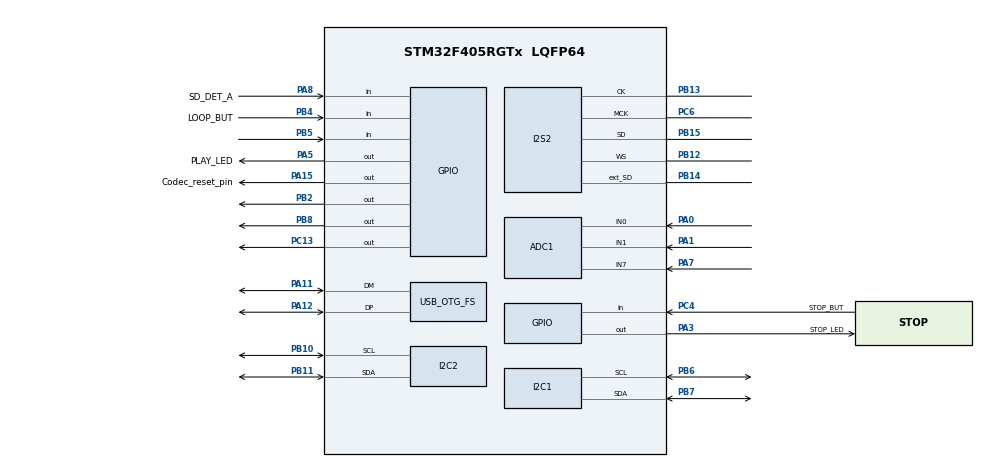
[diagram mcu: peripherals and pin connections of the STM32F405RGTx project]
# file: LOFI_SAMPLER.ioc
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ADC1.Channel-0\#ChannelRegularConversion=ADC_CHANNEL_0
ADC1.Channel-1\#ChannelRegularConversion=ADC_CHANNEL_1
ADC1.Channel-2\#ChannelRegularConversion=ADC_CHANNEL_7
ADC1.ClockPrescaler=ADC_CLOCK_SYNC_PCLK_DIV4
ADC1.DMAContinuousRequests=ENABLE
ADC1.ExternalTrigConv=ADC_EXTERNALTRIGCONV_T2_TRGO
ADC1.NbrOfConversion=3
ADC1.NbrOfConversionFlag=1
ADC1.Rank-0\#ChannelRegularConversion=1
ADC1.Rank-1\#ChannelRegularConversion=2
ADC1.Rank-2\#ChannelRegularConversion=3
ADC1.SamplingTime-0\#ChannelRegularConversion=ADC_SAMPLETIME_144CYCLES
ADC1.SamplingTime-1\#ChannelRegularConversion=ADC_SAMPLETIME_144CYCLES
ADC1.SamplingTime-2\#ChannelRegularConversion=ADC_SAMPLETIME_144CYCLES
ADC1.ScanConvMode=ENABLE
ADC1.master=1
Dma.ADC1.2.Direction=DMA_PERIPH_TO_MEMORY
Dma.ADC1.2.FIFOMode=DMA_FIFOMODE_DISABLE
Dma.ADC1.2.Instance=DMA2_Stream0
Dma.ADC1.2.MemDataAlignment=DMA_MDATAALIGN_HALFWORD
Dma.ADC1.2.MemInc=DMA_MINC_ENABLE
Dma.ADC1.2.Mode=DMA_CIRCULAR
Dma.ADC1.2.PeriphDataAlignment=DMA_PDATAALIGN_HALFWORD
Dma.ADC1.2.PeriphInc=DMA_PINC_DISABLE
Dma.ADC1.2.Priority=DMA_PRIORITY_LOW
Dma.I2S2_EXT_RX.1.Direction=DMA_PERIPH_TO_MEMORY
Dma.I2S2_EXT_RX.1.FIFOMode=DMA_FIFOMODE_DISABLE
Dma.I2S2_EXT_RX.1.Instance=DMA1_Stream3
Dma.I2S2_EXT_RX.1.MemDataAlignment=DMA_MDATAALIGN_HALFWORD
Dma.I2S2_EXT_RX.1.MemInc=DMA_MINC_ENABLE
Dma.I2S2_EXT_RX.1.Mode=DMA_CIRCULAR
Dma.I2S2_EXT_RX.1.PeriphDataAlignment=DMA_PDATAALIGN_HALFWORD
Dma.I2S2_EXT_RX.1.PeriphInc=DMA_PINC_DISABLE
Dma.I2S2_EXT_RX.1.Priority=DMA_PRIORITY_VERY_HIGH
Dma.Request0=SPI2_TX
Dma.Request1=I2S2_EXT_RX
Dma.Request2=ADC1
Dma.SPI2_TX.0.Direction=DMA_MEMORY_TO_PERIPH
Dma.SPI2_TX.0.FIFOMode=DMA_FIFOMODE_DISABLE
Dma.SPI2_TX.0.Instance=DMA1_Stream4
Dma.SPI2_TX.0.MemDataAlignment=DMA_MDATAALIGN_HALFWORD
Dma.SPI2_TX.0.MemInc=DMA_MINC_ENABLE
Dma.SPI2_TX.0.Mode=DMA_CIRCULAR
Dma.SPI2_TX.0.PeriphDataAlignment=DMA_PDATAALIGN_HALFWORD
Dma.SPI2_TX.0.PeriphInc=DMA_PINC_DISABLE
Dma.SPI2_TX.0.Priority=DMA_PRIORITY_VERY_HIGH
I2S2.AudioFreq=I2S_AUDIOFREQ_48K
I2S2.ErrorAudioFreq=1.72 %
I2S2.FullDuplexMode=I2S_FULLDUPLEXMODE_ENABLE
I2S2.Instance=SPI$Index
I2S2.RealAudioFreq=48.828 KHz
I2S2.VirtualMode=I2S_MODE_MASTER
Mcu.Family=STM32F4
Mcu.Name=STM32F405RGTx
Mcu.Package=LQFP64
NVIC.DMA1_Stream3_IRQn=true\:0\:0\:false\:false\:true\:false\:true\:true
NVIC.DMA1_Stream4_IRQn=true\:0\:0\:false\:false\:true\:false\:true\:true
NVIC.DMA2_Stream0_IRQn=true\:0\:0\:false\:false\:true\:false\:true\:true
NVIC.OTG_FS_IRQn=true\:0\:0\:false\:false\:true\:false\:true\:true
NVIC.PriorityGroup=NVIC_PRIORITYGROUP_4
PA0-WKUP.Signal=ADCx_IN0
PA1.Signal=ADCx_IN1
PA11.Mode=Device_Only
PA11.Signal=USB_OTG_FS_DM
PA12.Mode=Device_Only
PA12.Signal=USB_OTG_FS_DP
PA13.Mode=Serial_Wire
PA13.Signal=SYS_JTMS-SWDIO
PA14.Mode=Serial_Wire
PA14.Signal=SYS_JTCK-SWCLK
PA15.GPIO_Label=Codec_reset_pin
PA15.Signal=GPIO_Output
PA3.GPIO_Label=STOP_LED
PA3.Signal=GPIO_Output
PA5.GPIO_Label=PLAY_LED
PA5.Signal=GPIO_Output
PA7.Signal=ADCx_IN7
PA8.GPIO_Label=SD_DET_A
PA8.Signal=GPIO_Input
PB10.Mode=I2C
PB10.Signal=I2C2_SCL
PB11.Mode=I2C
PB11.Signal=I2C2_SDA
PB12.Mode=Full_Duplex_Master
PB12.Signal=I2S2_WS
PB13.Mode=Full_Duplex_Master
PB13.Signal=I2S2_CK
PB14.Mode=Full_Duplex_Master
PB14.Signal=I2S2_ext_SD
PB15.Mode=Full_Duplex_Master
PB15.Signal=I2S2_SD
PB2.Signal=GPIO_Output
PB3.Signal=SYS_JTDO-SWO
PB4.GPIO_Label=LOOP_BUT
PB4.Signal=GPIO_Input
PB5.Signal=GPIO_Input
PB6.Mode=I2C
PB6.Signal=I2C1_SCL
PB7.Mode=I2C
PB7.Signal=I2C1_SDA
PB8.Signal=GPIO_Output
PC13-ANTI_TAMP.Signal=GPIO_Output
PC4.GPIO_Label=STOP_BUT
PC4.Signal=GPIO_Input
PC6.Mode=Master_Clock_Activated
PC6.Signal=I2S2_MCK
PH0-OSC_IN.Mode=HSE-External-Oscillator
PH0-OSC_IN.Signal=RCC_OSC_IN
PH1-OSC_OUT.Mode=HSE-External-Oscillator
PH1-OSC_OUT.Signal=RCC_OSC_OUT
ProjectManager.HeapSize=0x200
ProjectManager.StackSize=0x400
ProjectManager.TargetToolchain=STM32CubeIDE
RCC.48MHZClocksFreq_Value=48000000
RCC.AHBFreq_Value=72000000
RCC.APB1CLKDivider=RCC_HCLK_DIV2
RCC.APB1Freq_Value=36000000
RCC.APB1TimFreq_Value=72000000
RCC.APB2Freq_Value=72000000
RCC.APB2TimFreq_Value=72000000
RCC.CortexFreq_Value=72000000
RCC.HCLKFreq_Value=72000000
RCC.HSE_VALUE=16000000
RCC.HSI_VALUE=16000000
RCC.LSE_VALUE=32768
RCC.PLLI2SN=50
RCC.PLLM=8
RCC.PLLN=72
RCC.PLLQ=3
RCC.SYSCLKFreq_VALUE=72000000
RCC.SYSCLKSource=RCC_SYSCLKSOURCE_PLLCLK
RCC.VCOOutputFreq_Value=144000000
SH.ADCx_IN0.0=ADC1_IN0,IN0
SH.ADCx_IN1.0=ADC1_IN1,IN1
SH.ADCx_IN7.0=ADC1_IN7,IN7
TIM2.Channel-PWM\ Generation1\ No\ Output=TIM_CHANNEL_1
TIM2.Period=500-1
TIM2.Prescaler=33600-1
TIM2.TIM_MasterOutputTrigger=TIM_TRGO_UPDATE
USB_DEVICE.CLASS_NAME_FS=CDC
USB_DEVICE.VirtualMode-CDC_FS=Cdc
USB_DEVICE.VirtualModeFS=Cdc_FS
USB_OTG_FS.VirtualMode=Device_Only
VP_TIM2_VS_ClockSourceINT.Mode=Internal
VP_TIM2_VS_no_output1.Mode=PWM Generation1 No Output
VP_USB_DEVICE_VS_USB_DEVICE_CDC_FS.Mode=CDC_FS
board=custom

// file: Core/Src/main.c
/* USER CODE BEGIN Header */
/**
  ******************************************************************************
  * @file           : main.c
  * @brief          : Main program body
  ******************************************************************************
  * @attention
  *
  * Copyright (c) 2025 STMicroelectronics.
  * All rights reserved.
  *
  * This software is licensed under terms that can be found in the LICENSE file
  * in the root directory of this software component.
  * If no LICENSE file comes with this software, it is provided AS-IS.
  *
  ******************************************************************************
  */
/* USER CODE END Header */
#include "main.h"
#include "usb_device.h"

/* USER CODE BEGIN Includes */
#include "I2C_Codec.h"
#include "ssd1306_fonts.h"
#include "ssd1306.h"
#include "usbd_cdc_if.h"
#include "IFX_Delay.h"
#include "Bitcrusher.h"
#include "IFX_Overdrive.h"
#include "IFX_Chorus.h"
/* USER CODE END Includes */

/* USER CODE BEGIN PD */
#define BUFFER_SIZE 256
#define INT16_TO_FLOAT (1.0f / 32768.0f)
#define FLOAT_TO_INT16 (32767.0f)
#define USB_BUFLEN 128
#define SAMPLING_FREQUENCY_HZ 48000.0f

/* USER CODE END PD */

ADC_HandleTypeDef hadc1;
DMA_HandleTypeDef hdma_adc1;

I2C_HandleTypeDef hi2c1;
I2C_HandleTypeDef hi2c2;

I2S_HandleTypeDef hi2s2;
DMA_HandleTypeDef hdma_spi2_tx;
DMA_HandleTypeDef hdma_i2s2_ext_rx;

TIM_HandleTypeDef htim2;

/* USER CODE BEGIN PV */
TLV_CODEC codec;
IFX_Overdrive od;
IFX_Delay dly;
IFX_Chorus ch;

//USB COM PORT
uint8_t usbTxBuf[USB_BUFLEN];
uint8_t usbTxBufLen;

int16_t adcData[BUFFER_SIZE];//audio
int16_t dacData[BUFFER_SIZE];//audio
uint16_t adcControlData[3]; //pots

static volatile int16_t *inBufPtr;
static volatile int16_t *outBufPtr = &dacData[0];

int bitDepth = 8;           // for example
int downsampleFactor = 8;   // for example

uint8_t dataReadyFlag;

uint8_t  fx_overdrive;
uint8_t  fx_delay;
uint8_t  fx_clean;
float outputVolume = 1;

/* USER CODE END PV */

void SystemClock_Config(void);
static void MX_GPIO_Init(void);
static void MX_DMA_Init(void);
static void MX_ADC1_Init(void);
static void MX_I2C1_Init(void);
static void MX_I2C2_Init(void);
static void MX_I2S2_Init(void);
static void MX_TIM2_Init(void);

/* USER CODE BEGIN 0 */
void DisplayPotBars(uint16_t *adcValues) {

	char *names[3] = { "Fc", "BITD", "PITCH" };

    ssd1306_Fill(Black);  // Clear screen once

    for (int i = 0; i < 3; i++) {
        uint8_t percent = (adcValues[i] * 100) / 4095;
       // uint8_t barWidth = (percent * 70) / 100;  // Bar max width 70 px

        uint8_t x = 0;
        uint8_t y = i * 20;  // 20 px vertical spacing

        // Draw bar outline
        ssd1306_DrawRectangle(x, y, 70, 18, White);

        // Draw filled portion of the bar
     /*   if (barWidth > 2) {
            ssd1306_FillRectangle(x + 1, y + 1, barWidth - 2, 16, White);
        }*/

        // Draw percentage text centered inside the bar
        char percentStr[6];
        sprintf(percentStr, "%3d%%", percent);

        // 4 chars * ~11 px = 44 px width approx
        uint8_t textX = x + (70 - 44) / 2;
        ssd1306_SetCursor(textX, y);
        ssd1306_WriteString(percentStr, Font_11x18, Black);  // Inverted color inside bar

        // Draw pot name on the right, starting at x=75, so 70 + 5 px margin
        ssd1306_SetCursor(75, y);
        ssd1306_WriteString(names[i], Font_11x18, White);

    }

    ssd1306_UpdateScreen();
}
void HAL_I2SEx_TxRxHalfCpltCallback(I2S_HandleTypeDef *hi2s){
	inBufPtr  =  &adcData[0];
	outBufPtr =  &dacData[0];

	dataReadyFlag = 1;
}
void HAL_I2SEx_TxRxCpltCallback(I2S_HandleTypeDef *hi2s){
	inBufPtr  =  &adcData[BUFFER_SIZE/2];
	outBufPtr =  &dacData[BUFFER_SIZE/2];

	dataReadyFlag = 1;
}

void ProcessData_Main() {
    float leftIn, leftOut, rightIn, rightOut;
    uint16_t raw1 = adcControlData[0];

    	float minVolume = 0;
    	float maxVolume = 1;

    	outputVolume = minVolume + ((float)raw1 / 4095.0f) *  (maxVolume - minVolume);

    for (uint8_t n = 0; n < (BUFFER_SIZE/2) - 1; n += 2) {
        // ---- LEFT ----
        leftIn = INT16_TO_FLOAT * inBufPtr[n];
        if (leftIn > 1.0f)
        	leftIn -= 2.0f;

        // start chain
        leftOut = leftIn;

        if (fx_overdrive) {
            leftOut = outputVolume* IFX_Overdrive_Update(&od, leftIn);
        }
        if (fx_delay) {
            leftOut = outputVolume * IFX_Delay_Update(&dly, leftIn);
        }

        if(fx_clean){
        	leftOut = outputVolume * IFX_Chorus_Update(&ch, leftIn);

        }
        outBufPtr[n] = (int16_t)(FLOAT_TO_INT16 * leftOut);

        // ---- RIGHT ----
        rightIn = INT16_TO_FLOAT * inBufPtr[n+1];
        if (rightIn > 1.0f)
        	rightIn -= 2.0f;

        rightOut = rightIn;

        outBufPtr[n+1] = (int16_t)(FLOAT_TO_INT16 * rightOut);
    }

    dataReadyFlag = 0;
}

/*void ProcessData_bitCrushed(){

    static float leftIn ,leftOut;
    static float rightIn ,rightOut;

    // Configure your effect parameters here

    for(uint8_t n=0; n<(BUFFER_SIZE/2)-1 ;n+=2){

        // ---- LEFT ----
        leftIn = INT16_TO_FLOAT * inBufPtr[n];
        if(leftIn > 1.0f) leftIn -= 2.0f;

        leftOut = Bitcrusher(leftIn, bitDepth, downsampleFactor,&hold_sample_L, &hold_count_L);

        outBufPtr[n] = (int16_t)(FLOAT_TO_INT16 * leftOut);

        // ---- RIGHT ----
        rightIn = INT16_TO_FLOAT * inBufPtr[n+1];
        if(rightIn > 1.0f) rightIn -= 2.0f;

        rightOut = Bitcrusher(rightIn, bitDepth, downsampleFactor,&hold_sample_R, &hold_count_R);

        outBufPtr[n+1] = (int16_t)(FLOAT_TO_INT16 * rightOut);
    }

    dataReadyFlag = 0;
}
*/
void UpdateDelayTime(void) {
    // Read raw ADC (0–4095)
    uint16_t raw = adcControlData[1];

    // Map it to a delay range, e.g. 10 ms – 1000 ms
    float minDelayMs = 1.0f;
    float maxDelayMs = 1000.0f;

    float delayMs = minDelayMs + ((float)raw / 4095.0f) * (maxDelayMs - minDelayMs);

    // Update delay length
    IFX_Delay_SetLength(&dly, delayMs, SAMPLING_FREQUENCY_HZ);
}
void UpdatepreGain(void) {
    // Read raw ADC (0–4095)
    uint16_t raw = adcControlData[1];

    // Map it to a delay range, e.g. 10 ms – 1000 ms
    float minGain = 1.0f;
    float maxGain = 10.0f;

    float Gain = minGain + ((float)raw / 4095.0f) * (maxGain - minGain);

    // Update delay length
    IFX_Overdrive_Set_preGain(&od, Gain);
}

uint8_t mode = 0; // 0 = STOP, 1 = LOOP, 2 = RECORD

void Switch_Modes(void) {
    // Check button states (active low assumed)
   if(dataReadyFlag){

	if (HAL_GPIO_ReadPin(GPIOC, GPIO_PIN_4) == GPIO_PIN_RESET) { // STOP BUTTON
		fx_overdrive = 1;
		fx_delay     = 0;
		fx_clean     = 0;
		HAL_GPIO_WritePin(GPIOA, GPIO_PIN_3, GPIO_PIN_SET);    // STOP LED ON
		HAL_GPIO_WritePin(GPIOC, GPIO_PIN_13, GPIO_PIN_RESET); // LOOP LED OFF
		HAL_GPIO_WritePin(GPIOB, GPIO_PIN_8, GPIO_PIN_RESET);  // RECORD LED OFF
		ssd1306_SetCursor(32, 32);
        ssd1306_WriteString("FUZZZ", Font_16x26, White);
        ssd1306_UpdateScreen();
        UpdatepreGain();
    }
    else if (HAL_GPIO_ReadPin(GPIOB, GPIO_PIN_4) == GPIO_PIN_RESET) { // LOOP BUTTON
    	fx_overdrive = 0;
    	fx_delay     = 0;
    	fx_clean     = 1;
        ssd1306_SetCursor(32, 32);
        ssd1306_WriteString("CLEAN", Font_16x26, White);
        ssd1306_UpdateScreen();
        HAL_GPIO_WritePin(GPIOA, GPIO_PIN_3, GPIO_PIN_RESET);  // STOP LED OFF
        HAL_GPIO_WritePin(GPIOC, GPIO_PIN_13, GPIO_PIN_SET);   // LOOP LED ON
        HAL_GPIO_WritePin(GPIOB, GPIO_PIN_8, GPIO_PIN_RESET);  // RECORD LED OFF
    }
    else if (HAL_GPIO_ReadPin(GPIOB, GPIO_PIN_5) == GPIO_PIN_RESET) { // RECORD BUTTON
    	fx_overdrive = 0;
    	fx_delay     = 1;
    	fx_clean     = 0;
    	HAL_GPIO_WritePin(GPIOA, GPIO_PIN_3, GPIO_PIN_RESET);  // STOP LED OFF
    	HAL_GPIO_WritePin(GPIOC, GPIO_PIN_13, GPIO_PIN_RESET); // LOOP LED OFF
    	HAL_GPIO_WritePin(GPIOB, GPIO_PIN_8, GPIO_PIN_SET);    // RECORD LED ON
    	ssd1306_SetCursor(32, 32);
        ssd1306_WriteString("DELAY", Font_16x26	, White);
        ssd1306_UpdateScreen();
        UpdateDelayTime();

    }
	ProcessData_Main();
  }
}

/* USER CODE END 0 */

int main(void)
{

  /* MCU Configuration--------------------------------------------------------*/

  /* Reset of all peripherals, Initializes the Flash interface and the Systick. */
  HAL_Init();

  /* Configure the system clock */
  SystemClock_Config();

  /* Initialize all configured peripherals */
  MX_GPIO_Init();
  MX_DMA_Init();
  MX_ADC1_Init();
  MX_I2C1_Init();
  MX_I2C2_Init();
  MX_I2S2_Init();
  MX_USB_DEVICE_Init();
  MX_TIM2_Init();
  /* USER CODE BEGIN 2 */

  Codec_Init(&codec, &hi2c2);

  HAL_Delay(50);
  ssd1306_Init();

  //ssd1306_Fill(White);
  //ssd1306_UpdateScreen();
 HAL_StatusTypeDef status_Data = HAL_I2SEx_TransmitReceive_DMA(&hi2s2, (uint16_t *) dacData, (uint16_t *) adcData, BUFFER_SIZE);
 HAL_ADC_Start_DMA(&hadc1, (uint32_t *) adcControlData, 3); //pots dma streams xd
 HAL_TIM_Base_Start(&htim2);

 IFX_Overdrive_Init(&od, 1.0f, 0.5f);
 IFX_Chorus_Init(&ch,10, 15, 20.0f, 20.0f,1.0f, 1.0f,5.0f, 5.0f,0.0f,SAMPLING_FREQUENCY_HZ);

 IFX_Delay_Init(&dly, 250.f, 0.5f, 0.5f,SAMPLING_FREQUENCY_HZ);

  /* USER CODE END 2 */

  /* Infinite loop */
  while (1)
  {

    /* USER CODE BEGIN 3 */

	Switch_Modes();

//LED PARTY FOLLOWING

	/*  HAL_Delay(50);

	  HAL_GPIO_TogglePin(GPIOB, GPIO_PIN_8);

	  HAL_Delay(250);

	  HAL_GPIO_TogglePin(GPIOC, GPIO_PIN_13);

	  HAL_Delay(250);

	  HAL_GPIO_TogglePin(GPIOA, GPIO_PIN_3);

	  HAL_Delay(250);

	  HAL_GPIO_TogglePin(GPIOA, GPIO_PIN_5);

	  HAL_Delay(250);

	*/

	  // USB COM PORT FOR TESTING
/*
	  usbTxBufLen = snprintf( ( char *)usbTxBuf , USB_BUFLEN , "%lu\r\n", HAL_GetTick() );
	  CDC_Transmit_FS(usbTxBuf, usbTxBufLen);
	  HAL_Delay(500);
*/
  }
  /* USER CODE END 3 */
}

void SystemClock_Config(void)
{
  RCC_OscInitTypeDef RCC_OscInitStruct = {0};
  RCC_ClkInitTypeDef RCC_ClkInitStruct = {0};

  /** Configure the main internal regulator output voltage
  */
  __HAL_RCC_PWR_CLK_ENABLE();
  __HAL_PWR_VOLTAGESCALING_CONFIG(PWR_REGULATOR_VOLTAGE_SCALE1);

  /** Initializes the RCC Oscillators according to the specified parameters
  * in the RCC_OscInitTypeDef structure.
  */
  RCC_OscInitStruct.OscillatorType = RCC_OSCILLATORTYPE_HSE;
  RCC_OscInitStruct.HSEState = RCC_HSE_ON;
  RCC_OscInitStruct.PLL.PLLState = RCC_PLL_ON;
  RCC_OscInitStruct.PLL.PLLSource = RCC_PLLSOURCE_HSE;
  RCC_OscInitStruct.PLL.PLLM = 8;
  RCC_OscInitStruct.PLL.PLLN = 168;
  RCC_OscInitStruct.PLL.PLLP = RCC_PLLP_DIV2;
  RCC_OscInitStruct.PLL.PLLQ = 7;
  if (HAL_RCC_OscConfig(&RCC_OscInitStruct) != HAL_OK)
  {
    Error_Handler();
  }

  /** Initializes the CPU, AHB and APB buses clocks
  */
  RCC_ClkInitStruct.ClockType = RCC_CLOCKTYPE_HCLK|RCC_CLOCKTYPE_SYSCLK
                              |RCC_CLOCKTYPE_PCLK1|RCC_CLOCKTYPE_PCLK2;
  RCC_ClkInitStruct.SYSCLKSource = RCC_SYSCLKSOURCE_PLLCLK;
  RCC_ClkInitStruct.AHBCLKDivider = RCC_SYSCLK_DIV1;
  RCC_ClkInitStruct.APB1CLKDivider = RCC_HCLK_DIV4;
  RCC_ClkInitStruct.APB2CLKDivider = RCC_HCLK_DIV2;

  if (HAL_RCC_ClockConfig(&RCC_ClkInitStruct, FLASH_LATENCY_5) != HAL_OK)
  {
    Error_Handler();
  }
}

static void MX_ADC1_Init(void)
{

  ADC_ChannelConfTypeDef sConfig = {0};

  /** Configure the global features of the ADC (Clock, Resolution, Data Alignment and number of conversion)
  */
  hadc1.Instance = ADC1;
  hadc1.Init.ClockPrescaler = ADC_CLOCK_SYNC_PCLK_DIV4;
  hadc1.Init.Resolution = ADC_RESOLUTION_12B;
  hadc1.Init.ScanConvMode = ENABLE;
  hadc1.Init.ContinuousConvMode = DISABLE;
  hadc1.Init.DiscontinuousConvMode = DISABLE;
  hadc1.Init.ExternalTrigConvEdge = ADC_EXTERNALTRIGCONVEDGE_RISING;
  hadc1.Init.ExternalTrigConv = ADC_EXTERNALTRIGCONV_T2_TRGO;
  hadc1.Init.DataAlign = ADC_DATAALIGN_RIGHT;
  hadc1.Init.NbrOfConversion = 3;
  hadc1.Init.DMAContinuousRequests = ENABLE;
  hadc1.Init.EOCSelection = ADC_EOC_SINGLE_CONV;
  if (HAL_ADC_Init(&hadc1) != HAL_OK)
  {
    Error_Handler();
  }

  /** Configure for the selected ADC regular channel its corresponding rank in the sequencer and its sample time.
  */
  sConfig.Channel = ADC_CHANNEL_0;
  sConfig.Rank = 1;
  sConfig.SamplingTime = ADC_SAMPLETIME_144CYCLES;
  if (HAL_ADC_ConfigChannel(&hadc1, &sConfig) != HAL_OK)
  {
    Error_Handler();
  }

  /** Configure for the selected ADC regular channel its corresponding rank in the sequencer and its sample time.
  */
  sConfig.Channel = ADC_CHANNEL_1;
  sConfig.Rank = 2;
  if (HAL_ADC_ConfigChannel(&hadc1, &sConfig) != HAL_OK)
  {
    Error_Handler();
  }

  /** Configure for the selected ADC regular channel its corresponding rank in the sequencer and its sample time.
  */
  sConfig.Channel = ADC_CHANNEL_7;
  sConfig.Rank = 3;
  if (HAL_ADC_ConfigChannel(&hadc1, &sConfig) != HAL_OK)
  {
    Error_Handler();
  }

}

static void MX_I2C1_Init(void)
{

  hi2c1.Instance = I2C1;
  hi2c1.Init.ClockSpeed = 100000;
  hi2c1.Init.DutyCycle = I2C_DUTYCYCLE_2;
  hi2c1.Init.OwnAddress1 = 0;
  hi2c1.Init.AddressingMode = I2C_ADDRESSINGMODE_7BIT;
  hi2c1.Init.DualAddressMode = I2C_DUALADDRESS_DISABLE;
  hi2c1.Init.OwnAddress2 = 0;
  hi2c1.Init.GeneralCallMode = I2C_GENERALCALL_DISABLE;
  hi2c1.Init.NoStretchMode = I2C_NOSTRETCH_DISABLE;
  if (HAL_I2C_Init(&hi2c1) != HAL_OK)
  {
    Error_Handler();
  }

}

static void MX_I2C2_Init(void)
{

  hi2c2.Instance = I2C2;
  hi2c2.Init.ClockSpeed = 100000;
  hi2c2.Init.DutyCycle = I2C_DUTYCYCLE_2;
  hi2c2.Init.OwnAddress1 = 0;
  hi2c2.Init.AddressingMode = I2C_ADDRESSINGMODE_7BIT;
  hi2c2.Init.DualAddressMode = I2C_DUALADDRESS_DISABLE;
  hi2c2.Init.OwnAddress2 = 0;
  hi2c2.Init.GeneralCallMode = I2C_GENERALCALL_DISABLE;
  hi2c2.Init.NoStretchMode = I2C_NOSTRETCH_DISABLE;
  if (HAL_I2C_Init(&hi2c2) != HAL_OK)
  {
    Error_Handler();
  }

}

static void MX_I2S2_Init(void)
{

  hi2s2.Instance = SPI2;
  hi2s2.Init.Mode = I2S_MODE_MASTER_TX;
  hi2s2.Init.Standard = I2S_STANDARD_PHILIPS;
  hi2s2.Init.DataFormat = I2S_DATAFORMAT_16B;
  hi2s2.Init.MCLKOutput = I2S_MCLKOUTPUT_ENABLE;
  hi2s2.Init.AudioFreq = I2S_AUDIOFREQ_48K;
  hi2s2.Init.CPOL = I2S_CPOL_LOW;
  hi2s2.Init.ClockSource = I2S_CLOCK_PLL;
  hi2s2.Init.FullDuplexMode = I2S_FULLDUPLEXMODE_ENABLE;
  if (HAL_I2S_Init(&hi2s2) != HAL_OK)
  {
    Error_Handler();
  }

}

static void MX_TIM2_Init(void)
{

  TIM_ClockConfigTypeDef sClockSourceConfig = {0};
  TIM_MasterConfigTypeDef sMasterConfig = {0};
  TIM_OC_InitTypeDef sConfigOC = {0};

  htim2.Instance = TIM2;
  htim2.Init.Prescaler = 33600-1;
  htim2.Init.CounterMode = TIM_COUNTERMODE_UP;
  htim2.Init.Period = 500-1;
  htim2.Init.ClockDivision = TIM_CLOCKDIVISION_DIV1;
  htim2.Init.AutoReloadPreload = TIM_AUTORELOAD_PRELOAD_DISABLE;
  if (HAL_TIM_Base_Init(&htim2) != HAL_OK)
  {
    Error_Handler();
  }
  sClockSourceConfig.ClockSource = TIM_CLOCKSOURCE_INTERNAL;
  if (HAL_TIM_ConfigClockSource(&htim2, &sClockSourceConfig) != HAL_OK)
  {
    Error_Handler();
  }
  if (HAL_TIM_PWM_Init(&htim2) != HAL_OK)
  {
    Error_Handler();
  }
  sMasterConfig.MasterOutputTrigger = TIM_TRGO_UPDATE;
  sMasterConfig.MasterSlaveMode = TIM_MASTERSLAVEMODE_DISABLE;
  if (HAL_TIMEx_MasterConfigSynchronization(&htim2, &sMasterConfig) != HAL_OK)
  {
    Error_Handler();
  }
  sConfigOC.OCMode = TIM_OCMODE_PWM1;
  sConfigOC.Pulse = 0;
  sConfigOC.OCPolarity = TIM_OCPOLARITY_HIGH;
  sConfigOC.OCFastMode = TIM_OCFAST_DISABLE;
  if (HAL_TIM_PWM_ConfigChannel(&htim2, &sConfigOC, TIM_CHANNEL_1) != HAL_OK)
  {
    Error_Handler();
  }

}

static void MX_DMA_Init(void)
{

  /* DMA controller clock enable */
  __HAL_RCC_DMA1_CLK_ENABLE();
  __HAL_RCC_DMA2_CLK_ENABLE();

  /* DMA interrupt init */
  /* DMA1_Stream3_IRQn interrupt configuration */
  HAL_NVIC_SetPriority(DMA1_Stream3_IRQn, 0, 0);
  HAL_NVIC_EnableIRQ(DMA1_Stream3_IRQn);
  /* DMA1_Stream4_IRQn interrupt configuration */
  HAL_NVIC_SetPriority(DMA1_Stream4_IRQn, 0, 0);
  HAL_NVIC_EnableIRQ(DMA1_Stream4_IRQn);
  /* DMA2_Stream0_IRQn interrupt configuration */
  HAL_NVIC_SetPriority(DMA2_Stream0_IRQn, 0, 0);
  HAL_NVIC_EnableIRQ(DMA2_Stream0_IRQn);

}

static void MX_GPIO_Init(void)
{
  GPIO_InitTypeDef GPIO_InitStruct = {0};

  /* GPIO Ports Clock Enable */
  __HAL_RCC_GPIOC_CLK_ENABLE();
  __HAL_RCC_GPIOH_CLK_ENABLE();
  __HAL_RCC_GPIOA_CLK_ENABLE();
  __HAL_RCC_GPIOB_CLK_ENABLE();

  /*Configure GPIO pin Output Level */
  HAL_GPIO_WritePin(GPIOC, GPIO_PIN_13, GPIO_PIN_RESET);

  /*Configure GPIO pin Output Level */
  HAL_GPIO_WritePin(GPIOA, STOP_LED_Pin|PLAY_LED_Pin|Codec_reset_pin_Pin, GPIO_PIN_RESET);

  /*Configure GPIO pin Output Level */
  HAL_GPIO_WritePin(GPIOB, GPIO_PIN_2|GPIO_PIN_8, GPIO_PIN_RESET);

  /*Configure GPIO pin : PC13 */
  GPIO_InitStruct.Pin = GPIO_PIN_13;
  GPIO_InitStruct.Mode = GPIO_MODE_OUTPUT_PP;
  GPIO_InitStruct.Pull = GPIO_NOPULL;
  GPIO_InitStruct.Speed = GPIO_SPEED_FREQ_LOW;
  HAL_GPIO_Init(GPIOC, &GPIO_InitStruct);

  /*Configure GPIO pins : STOP_LED_Pin PLAY_LED_Pin Codec_reset_pin_Pin */
  GPIO_InitStruct.Pin = STOP_LED_Pin|PLAY_LED_Pin|Codec_reset_pin_Pin;
  GPIO_InitStruct.Mode = GPIO_MODE_OUTPUT_PP;
  GPIO_InitStruct.Pull = GPIO_NOPULL;
  GPIO_InitStruct.Speed = GPIO_SPEED_FREQ_LOW;
  HAL_GPIO_Init(GPIOA, &GPIO_InitStruct);

  /*Configure GPIO pin : STOP_BUT_Pin */
  GPIO_InitStruct.Pin = STOP_BUT_Pin;
  GPIO_InitStruct.Mode = GPIO_MODE_INPUT;
  GPIO_InitStruct.Pull = GPIO_NOPULL;
  HAL_GPIO_Init(STOP_BUT_GPIO_Port, &GPIO_InitStruct);

  /*Configure GPIO pins : PB2 PB8 */
  GPIO_InitStruct.Pin = GPIO_PIN_2|GPIO_PIN_8;
  GPIO_InitStruct.Mode = GPIO_MODE_OUTPUT_PP;
  GPIO_InitStruct.Pull = GPIO_NOPULL;
  GPIO_InitStruct.Speed = GPIO_SPEED_FREQ_LOW;
  HAL_GPIO_Init(GPIOB, &GPIO_InitStruct);

  /*Configure GPIO pin : SD_DET_A_Pin */
  GPIO_InitStruct.Pin = SD_DET_A_Pin;
  GPIO_InitStruct.Mode = GPIO_MODE_INPUT;
  GPIO_InitStruct.Pull = GPIO_NOPULL;
  HAL_GPIO_Init(SD_DET_A_GPIO_Port, &GPIO_InitStruct);

  /*Configure GPIO pins : LOOP_BUT_Pin PB5 */
  GPIO_InitStruct.Pin = LOOP_BUT_Pin|GPIO_PIN_5;
  GPIO_InitStruct.Mode = GPIO_MODE_INPUT;
  GPIO_InitStruct.Pull = GPIO_NOPULL;
  HAL_GPIO_Init(GPIOB, &GPIO_InitStruct);

}

void Error_Handler(void)
{
  __disable_irq();
  while (1)
  {
  }
}
